VERSION 5.7 ;
  NOWIREEXTENSIONATPIN ON ;
  DIVIDERCHAR "/" ;
  BUSBITCHARS "[]" ;
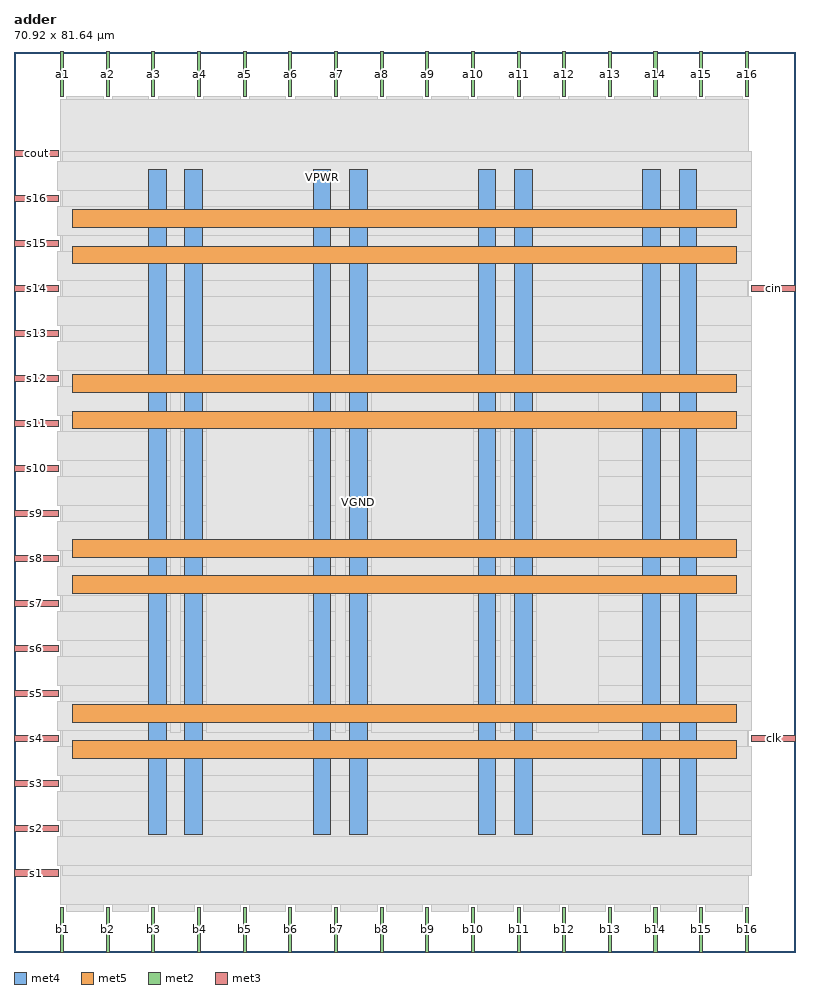
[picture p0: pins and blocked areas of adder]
MACRO adder
  CLASS BLOCK ;
  FOREIGN adder ;
  ORIGIN 0.000 0.000 ;
  SIZE 70.920 BY 81.640 ;
  PIN VGND
    DIRECTION INOUT ;
    USE GROUND ;
    PORT
      LAYER met4 ;
        RECT 15.495 10.640 17.095 70.960 ;
    END
    PORT
      LAYER met4 ;
        RECT 30.445 10.640 32.045 70.960 ;
    END
    PORT
      LAYER met4 ;
        RECT 45.395 10.640 46.995 70.960 ;
    END
    PORT
      LAYER met4 ;
        RECT 60.345 10.640 61.945 70.960 ;
    END
    PORT
      LAYER met5 ;
        RECT 5.280 20.855 65.560 22.455 ;
    END
    PORT
      LAYER met5 ;
        RECT 5.280 35.810 65.560 37.410 ;
    END
    PORT
      LAYER met5 ;
        RECT 5.280 50.765 65.560 52.365 ;
    END
    PORT
      LAYER met5 ;
        RECT 5.280 65.720 65.560 67.320 ;
    END
  END VGND
  PIN VPWR
    DIRECTION INOUT ;
    USE POWER ;
    PORT
      LAYER met4 ;
        RECT 12.195 10.640 13.795 70.960 ;
    END
    PORT
      LAYER met4 ;
        RECT 27.145 10.640 28.745 70.960 ;
    END
    PORT
      LAYER met4 ;
        RECT 42.095 10.640 43.695 70.960 ;
    END
    PORT
      LAYER met4 ;
        RECT 57.045 10.640 58.645 70.960 ;
    END
    PORT
      LAYER met5 ;
        RECT 5.280 17.555 65.560 19.155 ;
    END
    PORT
      LAYER met5 ;
        RECT 5.280 32.510 65.560 34.110 ;
    END
    PORT
      LAYER met5 ;
        RECT 5.280 47.465 65.560 49.065 ;
    END
    PORT
      LAYER met5 ;
        RECT 5.280 62.420 65.560 64.020 ;
    END
  END VPWR
  PIN a1
    DIRECTION INPUT ;
    USE SIGNAL ;
    ANTENNAGATEAREA 0.196500 ;
    PORT
      LAYER met2 ;
        RECT 4.230 77.640 4.510 81.640 ;
    END
  END a1
  PIN a10
    DIRECTION INPUT ;
    USE SIGNAL ;
    ANTENNAGATEAREA 0.196500 ;
    PORT
      LAYER met2 ;
        RECT 41.490 77.640 41.770 81.640 ;
    END
  END a10
  PIN a11
    DIRECTION INPUT ;
    USE SIGNAL ;
    ANTENNAGATEAREA 0.196500 ;
    PORT
      LAYER met2 ;
        RECT 45.630 77.640 45.910 81.640 ;
    END
  END a11
  PIN a12
    DIRECTION INPUT ;
    USE SIGNAL ;
    ANTENNAGATEAREA 0.196500 ;
    PORT
      LAYER met2 ;
        RECT 49.770 77.640 50.050 81.640 ;
    END
  END a12
  PIN a13
    DIRECTION INPUT ;
    USE SIGNAL ;
    ANTENNAGATEAREA 0.196500 ;
    PORT
      LAYER met2 ;
        RECT 53.910 77.640 54.190 81.640 ;
    END
  END a13
  PIN a14
    DIRECTION INPUT ;
    USE SIGNAL ;
    ANTENNAGATEAREA 0.196500 ;
    PORT
      LAYER met2 ;
        RECT 58.050 77.640 58.330 81.640 ;
    END
  END a14
  PIN a15
    DIRECTION INPUT ;
    USE SIGNAL ;
    ANTENNAGATEAREA 0.196500 ;
    PORT
      LAYER met2 ;
        RECT 62.190 77.640 62.470 81.640 ;
    END
  END a15
  PIN a16
    DIRECTION INPUT ;
    USE SIGNAL ;
    ANTENNAGATEAREA 0.196500 ;
    PORT
      LAYER met2 ;
        RECT 66.330 77.640 66.610 81.640 ;
    END
  END a16
  PIN a2
    DIRECTION INPUT ;
    USE SIGNAL ;
    ANTENNAGATEAREA 0.196500 ;
    PORT
      LAYER met2 ;
        RECT 8.370 77.640 8.650 81.640 ;
    END
  END a2
  PIN a3
    DIRECTION INPUT ;
    USE SIGNAL ;
    ANTENNAGATEAREA 0.196500 ;
    PORT
      LAYER met2 ;
        RECT 12.510 77.640 12.790 81.640 ;
    END
  END a3
  PIN a4
    DIRECTION INPUT ;
    USE SIGNAL ;
    ANTENNAGATEAREA 0.196500 ;
    PORT
      LAYER met2 ;
        RECT 16.650 77.640 16.930 81.640 ;
    END
  END a4
  PIN a5
    DIRECTION INPUT ;
    USE SIGNAL ;
    ANTENNAGATEAREA 0.196500 ;
    PORT
      LAYER met2 ;
        RECT 20.790 77.640 21.070 81.640 ;
    END
  END a5
  PIN a6
    DIRECTION INPUT ;
    USE SIGNAL ;
    ANTENNAGATEAREA 0.196500 ;
    PORT
      LAYER met2 ;
        RECT 24.930 77.640 25.210 81.640 ;
    END
  END a6
  PIN a7
    DIRECTION INPUT ;
    USE SIGNAL ;
    ANTENNAGATEAREA 0.196500 ;
    PORT
      LAYER met2 ;
        RECT 29.070 77.640 29.350 81.640 ;
    END
  END a7
  PIN a8
    DIRECTION INPUT ;
    USE SIGNAL ;
    ANTENNAGATEAREA 0.196500 ;
    PORT
      LAYER met2 ;
        RECT 33.210 77.640 33.490 81.640 ;
    END
  END a8
  PIN a9
    DIRECTION INPUT ;
    USE SIGNAL ;
    ANTENNAGATEAREA 0.196500 ;
    PORT
      LAYER met2 ;
        RECT 37.350 77.640 37.630 81.640 ;
    END
  END a9
  PIN b1
    DIRECTION INPUT ;
    USE SIGNAL ;
    ANTENNAGATEAREA 0.196500 ;
    PORT
      LAYER met2 ;
        RECT 4.230 0.000 4.510 4.000 ;
    END
  END b1
  PIN b10
    DIRECTION INPUT ;
    USE SIGNAL ;
    ANTENNAGATEAREA 0.196500 ;
    PORT
      LAYER met2 ;
        RECT 41.490 0.000 41.770 4.000 ;
    END
  END b10
  PIN b11
    DIRECTION INPUT ;
    USE SIGNAL ;
    ANTENNAGATEAREA 0.196500 ;
    PORT
      LAYER met2 ;
        RECT 45.630 0.000 45.910 4.000 ;
    END
  END b11
  PIN b12
    DIRECTION INPUT ;
    USE SIGNAL ;
    ANTENNAGATEAREA 0.196500 ;
    PORT
      LAYER met2 ;
        RECT 49.770 0.000 50.050 4.000 ;
    END
  END b12
  PIN b13
    DIRECTION INPUT ;
    USE SIGNAL ;
    ANTENNAGATEAREA 0.196500 ;
    PORT
      LAYER met2 ;
        RECT 53.910 0.000 54.190 4.000 ;
    END
  END b13
  PIN b14
    DIRECTION INPUT ;
    USE SIGNAL ;
    ANTENNAGATEAREA 0.196500 ;
    PORT
      LAYER met2 ;
        RECT 58.050 0.000 58.330 4.000 ;
    END
  END b14
  PIN b15
    DIRECTION INPUT ;
    USE SIGNAL ;
    ANTENNAGATEAREA 0.196500 ;
    PORT
      LAYER met2 ;
        RECT 62.190 0.000 62.470 4.000 ;
    END
  END b15
  PIN b16
    DIRECTION INPUT ;
    USE SIGNAL ;
    ANTENNAGATEAREA 0.196500 ;
    PORT
      LAYER met2 ;
        RECT 66.330 0.000 66.610 4.000 ;
    END
  END b16
  PIN b2
    DIRECTION INPUT ;
    USE SIGNAL ;
    ANTENNAGATEAREA 0.196500 ;
    PORT
      LAYER met2 ;
        RECT 8.370 0.000 8.650 4.000 ;
    END
  END b2
  PIN b3
    DIRECTION INPUT ;
    USE SIGNAL ;
    ANTENNAGATEAREA 0.196500 ;
    PORT
      LAYER met2 ;
        RECT 12.510 0.000 12.790 4.000 ;
    END
  END b3
  PIN b4
    DIRECTION INPUT ;
    USE SIGNAL ;
    ANTENNAGATEAREA 0.196500 ;
    PORT
      LAYER met2 ;
        RECT 16.650 0.000 16.930 4.000 ;
    END
  END b4
  PIN b5
    DIRECTION INPUT ;
    USE SIGNAL ;
    ANTENNAGATEAREA 0.196500 ;
    PORT
      LAYER met2 ;
        RECT 20.790 0.000 21.070 4.000 ;
    END
  END b5
  PIN b6
    DIRECTION INPUT ;
    USE SIGNAL ;
    ANTENNAGATEAREA 0.196500 ;
    PORT
      LAYER met2 ;
        RECT 24.930 0.000 25.210 4.000 ;
    END
  END b6
  PIN b7
    DIRECTION INPUT ;
    USE SIGNAL ;
    ANTENNAGATEAREA 0.196500 ;
    PORT
      LAYER met2 ;
        RECT 29.070 0.000 29.350 4.000 ;
    END
  END b7
  PIN b8
    DIRECTION INPUT ;
    USE SIGNAL ;
    ANTENNAGATEAREA 0.196500 ;
    PORT
      LAYER met2 ;
        RECT 33.210 0.000 33.490 4.000 ;
    END
  END b8
  PIN b9
    DIRECTION INPUT ;
    USE SIGNAL ;
    ANTENNAGATEAREA 0.196500 ;
    PORT
      LAYER met2 ;
        RECT 37.350 0.000 37.630 4.000 ;
    END
  END b9
  PIN cin
    DIRECTION INPUT ;
    USE SIGNAL ;
    ANTENNAGATEAREA 0.196500 ;
    PORT
      LAYER met3 ;
        RECT 66.920 59.880 70.920 60.480 ;
    END
  END cin
  PIN clk
    DIRECTION INPUT ;
    USE SIGNAL ;
    ANTENNAGATEAREA 0.852000 ;
    PORT
      LAYER met3 ;
        RECT 66.920 19.080 70.920 19.680 ;
    END
  END clk
  PIN cout
    DIRECTION OUTPUT ;
    USE SIGNAL ;
    ANTENNADIFFAREA 0.340600 ;
    PORT
      LAYER met3 ;
        RECT 0.000 72.120 4.000 72.720 ;
    END
  END cout
  PIN s1
    DIRECTION OUTPUT ;
    USE SIGNAL ;
    ANTENNADIFFAREA 0.340600 ;
    PORT
      LAYER met3 ;
        RECT 0.000 6.840 4.000 7.440 ;
    END
  END s1
  PIN s10
    DIRECTION OUTPUT ;
    USE SIGNAL ;
    ANTENNADIFFAREA 0.340600 ;
    PORT
      LAYER met3 ;
        RECT 0.000 43.560 4.000 44.160 ;
    END
  END s10
  PIN s11
    DIRECTION OUTPUT ;
    USE SIGNAL ;
    ANTENNADIFFAREA 0.340600 ;
    PORT
      LAYER met3 ;
        RECT 0.000 47.640 4.000 48.240 ;
    END
  END s11
  PIN s12
    DIRECTION OUTPUT ;
    USE SIGNAL ;
    ANTENNADIFFAREA 0.340600 ;
    PORT
      LAYER met3 ;
        RECT 0.000 51.720 4.000 52.320 ;
    END
  END s12
  PIN s13
    DIRECTION OUTPUT ;
    USE SIGNAL ;
    ANTENNADIFFAREA 0.340600 ;
    PORT
      LAYER met3 ;
        RECT 0.000 55.800 4.000 56.400 ;
    END
  END s13
  PIN s14
    DIRECTION OUTPUT ;
    USE SIGNAL ;
    ANTENNADIFFAREA 0.340600 ;
    PORT
      LAYER met3 ;
        RECT 0.000 59.880 4.000 60.480 ;
    END
  END s14
  PIN s15
    DIRECTION OUTPUT ;
    USE SIGNAL ;
    ANTENNADIFFAREA 0.340600 ;
    PORT
      LAYER met3 ;
        RECT 0.000 63.960 4.000 64.560 ;
    END
  END s15
  PIN s16
    DIRECTION OUTPUT ;
    USE SIGNAL ;
    ANTENNADIFFAREA 0.340600 ;
    PORT
      LAYER met3 ;
        RECT 0.000 68.040 4.000 68.640 ;
    END
  END s16
  PIN s2
    DIRECTION OUTPUT ;
    USE SIGNAL ;
    ANTENNADIFFAREA 0.340600 ;
    PORT
      LAYER met3 ;
        RECT 0.000 10.920 4.000 11.520 ;
    END
  END s2
  PIN s3
    DIRECTION OUTPUT ;
    USE SIGNAL ;
    ANTENNADIFFAREA 0.340600 ;
    PORT
      LAYER met3 ;
        RECT 0.000 15.000 4.000 15.600 ;
    END
  END s3
  PIN s4
    DIRECTION OUTPUT ;
    USE SIGNAL ;
    ANTENNADIFFAREA 0.340600 ;
    PORT
      LAYER met3 ;
        RECT 0.000 19.080 4.000 19.680 ;
    END
  END s4
  PIN s5
    DIRECTION OUTPUT ;
    USE SIGNAL ;
    ANTENNADIFFAREA 0.340600 ;
    PORT
      LAYER met3 ;
        RECT 0.000 23.160 4.000 23.760 ;
    END
  END s5
  PIN s6
    DIRECTION OUTPUT ;
    USE SIGNAL ;
    ANTENNADIFFAREA 0.340600 ;
    PORT
      LAYER met3 ;
        RECT 0.000 27.240 4.000 27.840 ;
    END
  END s6
  PIN s7
    DIRECTION OUTPUT ;
    USE SIGNAL ;
    ANTENNADIFFAREA 0.340600 ;
    PORT
      LAYER met3 ;
        RECT 0.000 31.320 4.000 31.920 ;
    END
  END s7
  PIN s8
    DIRECTION OUTPUT ;
    USE SIGNAL ;
    ANTENNADIFFAREA 0.340600 ;
    PORT
      LAYER met3 ;
        RECT 0.000 35.400 4.000 36.000 ;
    END
  END s8
  PIN s9
    DIRECTION OUTPUT ;
    USE SIGNAL ;
    ANTENNADIFFAREA 0.340600 ;
    PORT
      LAYER met3 ;
        RECT 0.000 39.480 4.000 40.080 ;
    END
  END s9
  OBS
      LAYER nwell ;
        RECT 5.330 10.795 65.510 70.805 ;
      LAYER li1 ;
        RECT 5.520 10.795 65.320 70.805 ;
      LAYER met1 ;
        RECT 4.210 10.640 66.630 71.700 ;
      LAYER met2 ;
        RECT 4.790 77.360 8.090 77.640 ;
        RECT 8.930 77.360 12.230 77.640 ;
        RECT 13.070 77.360 16.370 77.640 ;
        RECT 17.210 77.360 20.510 77.640 ;
        RECT 21.350 77.360 24.650 77.640 ;
        RECT 25.490 77.360 28.790 77.640 ;
        RECT 29.630 77.360 32.930 77.640 ;
        RECT 33.770 77.360 37.070 77.640 ;
        RECT 37.910 77.360 41.210 77.640 ;
        RECT 42.050 77.360 45.350 77.640 ;
        RECT 46.190 77.360 49.490 77.640 ;
        RECT 50.330 77.360 53.630 77.640 ;
        RECT 54.470 77.360 57.770 77.640 ;
        RECT 58.610 77.360 61.910 77.640 ;
        RECT 62.750 77.360 66.050 77.640 ;
        RECT 4.230 4.280 66.600 77.360 ;
        RECT 4.790 3.670 8.090 4.280 ;
        RECT 8.930 3.670 12.230 4.280 ;
        RECT 13.070 3.670 16.370 4.280 ;
        RECT 17.210 3.670 20.510 4.280 ;
        RECT 21.350 3.670 24.650 4.280 ;
        RECT 25.490 3.670 28.790 4.280 ;
        RECT 29.630 3.670 32.930 4.280 ;
        RECT 33.770 3.670 37.070 4.280 ;
        RECT 37.910 3.670 41.210 4.280 ;
        RECT 42.050 3.670 45.350 4.280 ;
        RECT 46.190 3.670 49.490 4.280 ;
        RECT 50.330 3.670 53.630 4.280 ;
        RECT 54.470 3.670 57.770 4.280 ;
        RECT 58.610 3.670 61.910 4.280 ;
        RECT 62.750 3.670 66.050 4.280 ;
      LAYER met3 ;
        RECT 4.400 71.720 66.920 72.585 ;
        RECT 3.990 69.040 66.920 71.720 ;
        RECT 4.400 67.640 66.920 69.040 ;
        RECT 3.990 64.960 66.920 67.640 ;
        RECT 4.400 63.560 66.920 64.960 ;
        RECT 3.990 60.880 66.920 63.560 ;
        RECT 4.400 59.480 66.520 60.880 ;
        RECT 3.990 56.800 66.920 59.480 ;
        RECT 4.400 55.400 66.920 56.800 ;
        RECT 3.990 52.720 66.920 55.400 ;
        RECT 4.400 51.320 66.920 52.720 ;
        RECT 3.990 48.640 66.920 51.320 ;
        RECT 4.400 47.240 66.920 48.640 ;
        RECT 3.990 44.560 66.920 47.240 ;
        RECT 4.400 43.160 66.920 44.560 ;
        RECT 3.990 40.480 66.920 43.160 ;
        RECT 4.400 39.080 66.920 40.480 ;
        RECT 3.990 36.400 66.920 39.080 ;
        RECT 4.400 35.000 66.920 36.400 ;
        RECT 3.990 32.320 66.920 35.000 ;
        RECT 4.400 30.920 66.920 32.320 ;
        RECT 3.990 28.240 66.920 30.920 ;
        RECT 4.400 26.840 66.920 28.240 ;
        RECT 3.990 24.160 66.920 26.840 ;
        RECT 4.400 22.760 66.920 24.160 ;
        RECT 3.990 20.080 66.920 22.760 ;
        RECT 4.400 18.680 66.520 20.080 ;
        RECT 3.990 16.000 66.920 18.680 ;
        RECT 4.400 14.600 66.920 16.000 ;
        RECT 3.990 11.920 66.920 14.600 ;
        RECT 4.400 10.520 66.920 11.920 ;
        RECT 3.990 7.840 66.920 10.520 ;
        RECT 4.400 6.975 66.920 7.840 ;
      LAYER met4 ;
        RECT 14.195 19.895 15.095 50.825 ;
        RECT 17.495 19.895 26.745 50.825 ;
        RECT 29.145 19.895 30.045 50.825 ;
        RECT 32.445 19.895 41.695 50.825 ;
        RECT 44.095 19.895 44.995 50.825 ;
        RECT 47.395 19.895 53.065 50.825 ;
  END
END adder
END LIBRARY

